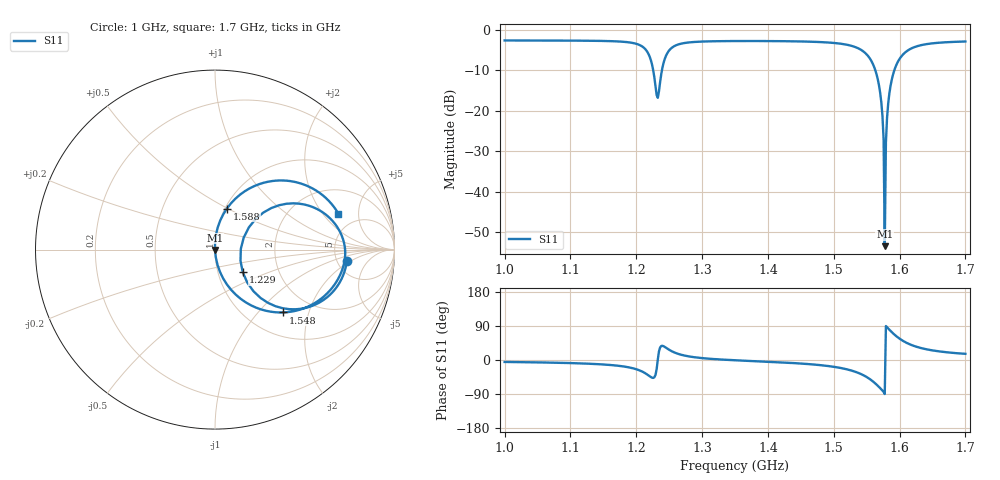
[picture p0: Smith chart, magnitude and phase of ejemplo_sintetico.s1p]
! MUESTRA SINTETICA - no es una medicion real
# Hz S RI R 50
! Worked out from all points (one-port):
!   401 points, 1 GHz to 1.7 GHz, reference 50 ohm
!   lowest |S11| = -53.5 dB at 1.577 GHz (marker M1), VSWR 1.00, Z = 50 - j0.211 ohm
!   |S11| at or under -10 dB: 1.226 GHz to 1.239 GHz (13.31 MHz wide, 1.08 % of centre); 1.563 GHz to 1.592 GHz (28.98 MHz wide, 1.84 % of centre)
!   S11 on the Smith chart (normalised r, x): 1 GHz: 6.10, -1.76; 1.229 GHz: 1.31, -0.35; 1.548 GHz: 1.45, -1.38; 1.588 GHz: 1.02, +0.50; 1.7 GHz: 3.53, +2.91
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1e9  0.7345 -0.0659
1.0875e9  0.7286 -0.0968
1.175e9  0.6885 -0.1933
1.1995e9  0.614 -0.2739
1.2135e9  0.4751 -0.3302
1.22225e9  0.2962 -0.2973
1.22925e9  0.1548 -0.1265
1.2345e9  0.1601 0.0674
1.24325e9  0.3577 0.2473
1.25025e9  0.4991 0.251
1.2625e9  0.6248 0.189
1.2905e9  0.7034 0.0842
1.35e9  0.7253 -0.00868
1.4375e9  0.713 -0.0994
1.525e9  0.57 -0.2889
1.54775e9  0.3802 -0.3501
1.55825e9  0.2284 -0.3232
1.567e9  0.0904 -0.2248
1.57225e9  0.0278 -0.1242
1.574e9  0.014 -0.0851
1.5775e9  7e-06 -0.00211
1.581e9  0.00521 0.0819
1.58275e9  0.0148 0.1222
1.588e9  0.0664 0.2288
1.5985e9  0.2196 0.3542
1.6125e9  0.4008 0.3838
1.644e9  0.596 0.306
1.7e9  0.6871 0.2009
